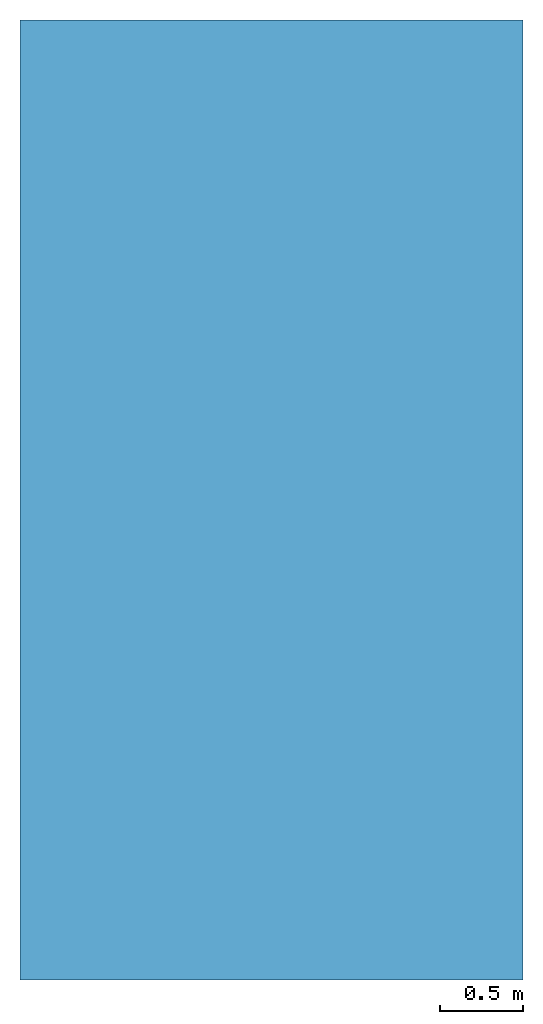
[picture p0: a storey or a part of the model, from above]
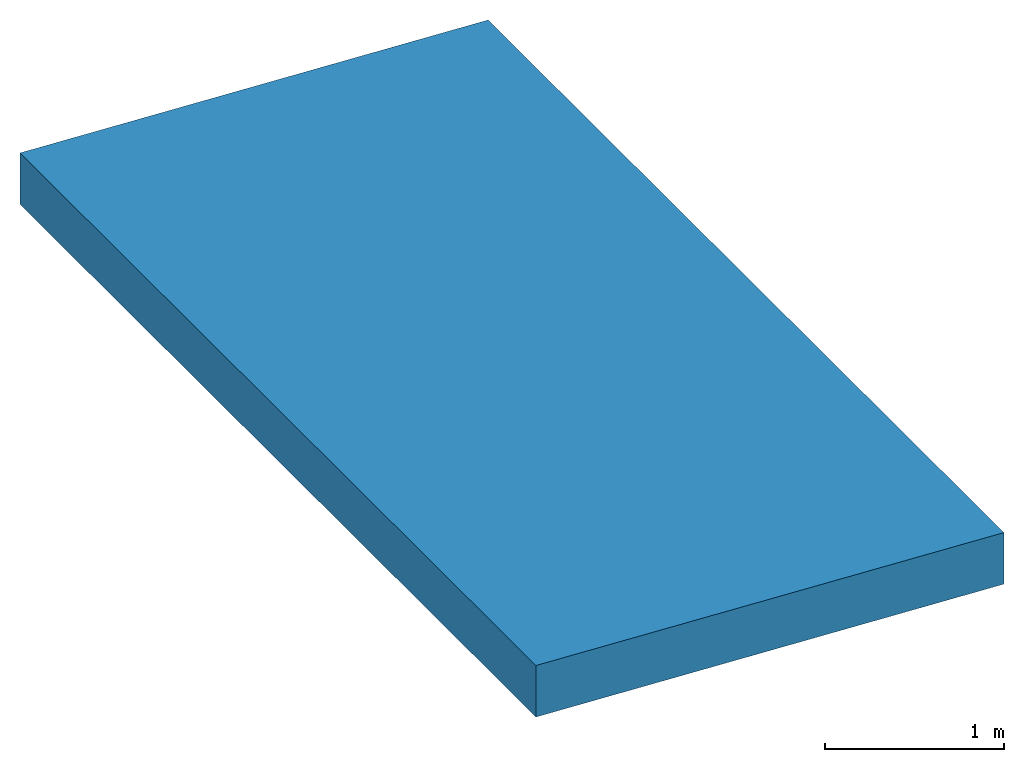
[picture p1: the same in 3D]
Properties of the parts of a building model (IFC2X3)

# File
Description: ViewDefinition [CoordinationView_V2.0], RevitIdentifiers [ContentGUID: b1a34cb4-f0af-4403-8faa-9d45a9ffd249, VersionGUID: 58a498d6-14ff-4763-b198-2685bdfd64d7, NumberOfSaves: 203], CoordinateReference [CoordinateBase: Shared Coordinates]
File name: Kinn servicebygg V9.ifc
Time: 2026-09-17T11:39:23+01:00
Written by: ODA SDAI 25.12
Made in: Autodesk - Revit 26.5.0.55 (ENU) - 26.5.0.55

# IfcProject
LongName: Prosjektnavn; Phase: Prosjektstatus

# IfcSite, Default
RefLatitude: 59, 55, 0, 119999; RefLongitude: 10, 44, 59, 999999; RefElevation: 0 mm

# IfcBuilding
Pset_BuildingCommon - NumberOfStoreys: 8

# IfcBuildingStorey (8)
Pset_AirSideSystemInformation - sets with these values: 2
Name | LongName = Name | Elevation (mm)
Kjeller | Kjeller | -3000
Et. 1 | Et. 1 | 0
Hems plan | Hems plan | 2700
Et. 2 | Et. 2 | 3100
Et. 3 | Et. 3 | 6000
Et. 4 | Et. 4 | 9000
Et. 5 | Et. 5 | 12000
Tak | Tak | 15000

# IfcSpace: Bad 106:843246, 106
In: Et. 1
LongName: Bad; InteriorOrExteriorSpace: INTERNAL
Pset_AirSideSystemInformation - Name: Bad; sets with these values: 2
Pset_SpaceCommon - Reference: Bad 106

# IfcSpace: HCWC 105:843243, 105
In: Et. 1
LongName: HCWC; InteriorOrExteriorSpace: INTERNAL
Pset_AirSideSystemInformation - Name: HCWC; sets with these values: 2
Pset_SpaceCommon - Reference: HCWC 105

# IfcSpace: Lager/tek. 116:884795, 116
In: Et. 1
LongName: Lager/tek.; InteriorOrExteriorSpace: INTERNAL
Pset_AirSideSystemInformation - Name: Lager/tek.; sets with these values: 2
Pset_SpaceCommon - Reference: Lager/tek. 116

# IfcSpace: Oppholdsrom 107:843249, 107
In: Et. 1
LongName: Oppholdsrom; InteriorOrExteriorSpace: INTERNAL
Pset_AirSideSystemInformation - Name: Oppholdsrom; sets with these values: 2
Pset_SpaceCommon - Reference: Oppholdsrom 107

# IfcSpace: WC 101:843231, 101
In: Et. 1
LongName: WC; InteriorOrExteriorSpace: INTERNAL
Pset_AirSideSystemInformation - Name: WC; sets with these values: 2
Pset_SpaceCommon - Reference: WC 101

# IfcSpace: WC 102:843234, 102
In: Et. 1
LongName: WC; InteriorOrExteriorSpace: INTERNAL
Pset_AirSideSystemInformation - Name: WC; sets with these values: 2
Pset_SpaceCommon - Reference: WC 102

# IfcSpace: WC 103:843237, 103
In: Et. 1
LongName: WC; InteriorOrExteriorSpace: INTERNAL
Pset_AirSideSystemInformation - Name: WC; sets with these values: 2
Pset_SpaceCommon - Reference: WC 103

# IfcBeam: Betong Rektangulær:Mønedrager 90x400, Betong Rektangulær:Mønedrager 90x400:924910
In: Et. 1
Type - PredefinedType: BEAM
Type - Pset_BeamCommon - LoadBearing: yes
Material: Tre - Kirsebær
Pset_BeamCommon - IsExternal: no; Slope: 0 deg; Reference: Mønedrager 90x400; Span: 12300 mm
Pset_QuantityTakeOff - Reference: Mønedrager 90x400; sets with these values: 2

# IfcBuildingElementProxy: Hvitevare - Oppvaskmaskin for integrering:600 mm, Hvitevare - Oppvaskmaskin for integrering:600 mm:955397
In: 107
Type - Material: Kjøkken - Hvitevarer
Pset_BuildingElementProxyCommon - Reference: 600 mm; sets with these values: 2

# IfcBuildingElementProxy: RIR_Rør-i-rør_Vegghengt:120x550x500 8rør Ø30, RIR_Rør-i-rør_Vegghengt:120x550x500 8rør Ø30:983592
In: 105
Type - Material: Sort, Hvit
Pset_BuildingElementProxyCommon - Reference: 120x550x500 8rør Ø30; sets with these values: 2

# IfcBuildingElementProxy: Sikringsskap Vegghengt:210x480x920, Sikringsskap Vegghengt:210x480x920:976827
In: 116
Type - Material: Sort, Hvit
Pset_BuildingElementProxyCommon - Reference: 210x480x920; sets with these values: 2

# IfcBuildingElementProxy: Vaskesøyle:Vaskesøyle, Vaskesøyle:Vaskesøyle:884217
In: 106
Type - Material: Bad-Vask-Maskin-Hvit, Stål-Børstet, Plastikk - Sort, Bad-Vask-Maskin-Glass
Pset_BuildingElementProxyCommon - Reference: Vaskesøyle; sets with these values: 2

# IfcColumn: Betong Rektangulær-Søyle:90x90 (6)
In: Et. 1
Type - PredefinedType: COLUMN; Material: Maling mørkegrå(1)
Type - Pset_ColumnCommon - LoadBearing: yes
Pset_ColumnCommon - IsExternal: no; Reference: 90x90; Slope: 0 deg
Pset_QuantityTakeOff - Reference: 90x90; sets with these values: 2
Name (Betong Rektangulær-Søyle:90x90:...)
817801
897383
936991
937197
937405
937572

# IfcCovering: Fascia:Møne, Fascia:Møne:924337
In: Et. 2
Type - Pset_CoveringCommon - Material: Metall - Takrenne
Material: Metall - Takrenne
Pset_CoveringCommon - Reference: Møne; sets with these values: 2

# IfcCovering: Fascia:Vindski (2)
In: Et. 1
Type - Pset_CoveringCommon - Material: Maling mørkegrå(1)
Material: Maling mørkegrå(1)
Pset_CoveringCommon - Reference: Vindski; sets with these values: 2
Name (Fascia:Vindski:...)
857847
906300

# IfcDistributionPort, Port_964572_1
Description: Flow; FlowDirection: SOURCEANDSINK

# IfcDoor: ID Hel:10x21M 2, ID Hel:10x21M 2:897865
In: Et. 1
Type - OperationType: SINGLE_SWING_RIGHT; ParameterTakesPrecedence: no; Sizeable: no; Material: Dør - Håndtak, Tre - Kirsebær
Type - ID Hel:10x21M 2:897865:1 - PanelOperation: SWINGING
OverallHeight: 2100 mm; OverallWidth: 1010 mm
Pset_DoorCommon - IsExternal: no; Reference: 10x21M 2
Pset_QuantityTakeOff - Reference: 10x21M 2

# IfcDoor: YD Glass:10x21M, YD Glass:10x21M:815108
In: Et. 1
Type - OperationType: SINGLE_SWING_RIGHT; ParameterTakesPrecedence: no; Sizeable: no; Material: Dør - Håndtak, Glass - Klart, Maling mørkegrå
Type - YD Glass:10x21M:815108:1 - PanelOperation: SWINGING
OverallHeight: 2090 mm; OverallWidth: 990 mm
Pset_DoorCommon - IsExternal: yes; Reference: 10x21M
Pset_QuantityTakeOff - Reference: 10x21M

# IfcDoor: YD Hel:10x21M (4)
In: Et. 1
Type - OperationType: SINGLE_SWING_LEFT; ParameterTakesPrecedence: no; Sizeable: no; Material: Focus - Dør - Håndtak, Maling mørkegrå, Dør - Terskel - Eik
Type - YD Hel:10x21M:815473:1 - PanelOperation: SWINGING
OverallHeight: 2090 mm; OverallWidth: 990 mm
Pset_DoorCommon - IsExternal: yes; Reference: 10x21M
Pset_QuantityTakeOff - Reference: 10x21M
Name (YD Hel:10x21M:...)
815473
815539
815673
815707

# IfcDoor: YD dobbel hel omramming:18x21M, YD dobbel hel omramming:18x21M:934386
In: Et. 1
Type - OperationType: DOUBLE_DOOR_SINGLE_SWING; ParameterTakesPrecedence: no; Sizeable: no; Material: Focus - Dør - Håndtak, Vegg - Dobbelfals Stående Kledning - Mørkegrå, Focus - Dør - Terskel - Eik
Type - YD dobbel hel omramming:18x21M:934386:1 - PanelOperation: SWINGING
OverallHeight: 2100 mm; OverallWidth: 1810 mm
Pset_DoorCommon - IsExternal: yes; Reference: 18x21M
Pset_QuantityTakeOff - Reference: 18x21M

# IfcFlowSegment: Gutter:Takrenne, Gutter:Takrenne:820507
In: Et. 1
Type - PredefinedType: GUTTER
Pset_DistributionFlowElementCommon - Reference: Takrenne; sets with these values: 2
Pset_FlowSegmentDuctSegment - Length: 26160 mm; sets with these values: 2
Pset_PipeSegmentTypeGutter - Slope: 61.647 deg

# IfcFlowSegment: Gutter:Takrenne beslag, Gutter:Takrenne beslag:820509
In: Et. 1
Type - PredefinedType: GUTTER
Pset_DistributionFlowElementCommon - Reference: Takrenne beslag; sets with these values: 2
Pset_FlowSegmentDuctSegment - Length: 26160 mm; sets with these values: 2
Pset_PipeSegmentTypeGutter - Slope: 0 deg

# IfcFlowTerminal: 7318_IfoSign_vask_500x310_mm_02:Med hanehul i højre side og overløb (3)
Type - Material: Bad-Innredning-Krom, <Unnamed>
Type - Pset_ManufacturerTypeInformation - Manufacturer: Ifö
Pset_DistributionFlowElementCommon - Reference: Med hanehul i højre side og overløb; sets with these values: 2
Name (7318_IfoSign_vask_500x310_mm_02:Med hanehul i højre side og overløb:...) | In
887691 | 103
887748 | 102
887800 | 101

# IfcFlowTerminal: Dusjhjørne_45:900x900mm, Dusjhjørne_45:900x900mm:976009
In: 106
Type - Material: Bad-Innredning-Krom, Bad-Innredning-dusjkabinett-Hvit, Bad-Innredning-Glass-Klar
Pset_DistributionFlowElementCommon - Reference: 900x900mm; sets with these values: 2

# IfcFlowTerminal: Focus - Skyllekar:65,5x50,5, Focus - Skyllekar:65,5x50,5:983081
In: 116
Type - Material: Metall - Polert Fin, Metall - Polert
Pset_DistributionFlowElementCommon - Reference: 65,5x50,5; sets with these values: 2

# IfcFlowTerminal: Focus - Vask:500x350, Focus - Vask:500x350:884095
In: 106
Type - Material: Focus - Material - Krom kran, Focus - Material - WC vask
Pset_DistributionFlowElementCommon - Reference: 500x350; sets with these values: 2

# IfcFlowTerminal: Focus-Toalett Veggmontert 2:Sittehøyde 420 (4)
Type - Material: Focus - VVS - Toalett lokk, Focus - VVS - Krom, Focus - VVS - Toalett
Pset_DistributionFlowElementCommon - Reference: Sittehøyde 420; sets with these values: 2
Name (Focus-Toalett Veggmontert 2:Sittehøyde 420:...) | In
883755 | 106
887868 | 101
887916 | 102
887976 | 103

# IfcFlowTerminal: GARDEN TAP 0153A03-01BVA03:0153A03, GARDEN TAP 0153A03-01BVA03:0153A03:964572
In: Et. 1
Type - Material: Brass, Nickel
Type - Pset_ManufacturerTypeInformation - Manufacturer: SOPAL
Material: Nickel, Chrome, RGB 255-000-000
Pset_DistributionFlowElementCommon - Reference: 0153A03; sets with these values: 2

# IfcFlowTerminal: Klassisk - Kjøkkenvask 1,5 kum:600mm høyre, Klassisk - Kjøkkenvask 1,5 kum:600mm høyre:958605
In: 107
Type - Material: Steel, Chrome Plated, Focus - Kjøkken - Kran, <Unnamed>, Focus - Kjøkken - Vask
Pset_DistributionFlowElementCommon - Reference: 600mm høyre; sets with these values: 2

# IfcFlowTerminal: Toalett HC veggmontert:Toalett HC veggmontert, Toalett HC veggmontert:Toalett HC veggmontert:868754
In: 105
Type - Material: Bad-Innredning-Håndstøtter-Hvit, Focus - VVS - Toalett, Focus - VVS - Toalett lokk, Bad-Innredning-Håndstøtter-Håndtak, Focus - VVS - Krom
Pset_DistributionFlowElementCommon - Reference: Toalett HC veggmontert; sets with these values: 2

# IfcFlowTerminal: VV-Bereder:315_VVB_120, VV-Bereder:315_VVB_120:976469
In: Et. 2
Type - Material: VVS-Bereder-Hvit
Pset_DistributionFlowElementCommon - Reference: 315_VVB_120; sets with these values: 2

# IfcFlowTerminal: Vask HC:600x600, Vask HC:600x600:870789
In: 105
Type - Material: Bad-Innredning-Krom, Bad-Innredning-Porselen
Pset_DistributionFlowElementCommon - Reference: 600x600; sets with these values: 2

# IfcFurnishingElement: Focus - Håndtak Skap:Håndtak skap (7)
In: 107
Type - Material: Focus - Kjøkken - Håndtak
Pset_QuantityTakeOff - Reference: Håndtak skap
Name (Focus - Håndtak Skap:Håndtak skap:...)
860161
860178
898565
905538
905934
907062
907970

# IfcFurnishingElement: Focus - Håndtak Skuff:Håndtak skuff, Focus - Håndtak Skuff:Håndtak skuff:955396
In: 107
Type - Material: Focus - Kjøkken - Håndtak
Pset_QuantityTakeOff - Reference: Håndtak skuff

# IfcFurnishingElement: Focus - Kjøkken - Benkeplate:Focus - Kjøkken - Benkeplate, Focus - Kjøkken - Benkeplate:Focus - Kjøkken - Benkeplate:863563
In: 107
Type - Material: Focus - Material - Benkeplate
Pset_QuantityTakeOff - Reference: Focus - Kjøkken - Benkeplate

# IfcFurnishingElement: Focus - Kjøkken - Benkeskap 1 dør:400 mm, Focus - Kjøkken - Benkeskap 1 dør:400 mm:898564
In: 107
Type - Material: Focus - Kjøkken - Front, Focus - Kjøkken - Skapstamme
Pset_QuantityTakeOff - Reference: 400 mm

# IfcFurnishingElement: Focus - Kjøkken - Benkeskap 1 dør:600 mm (2)
In: 107
Type - Material: Focus - Kjøkken - Front, Focus - Kjøkken - Skapstamme
Pset_QuantityTakeOff - Reference: 600 mm
Name (Focus - Kjøkken - Benkeskap 1 dør:600 mm:...)
860160
860177

# IfcFurnishingElement: Focus - Kjøkken - Oppvaskmaskin Itegrert:600 mm, Focus - Kjøkken - Oppvaskmaskin Itegrert:600 mm:955395
In: 107
Type - Material: Focus - Kjøkken - Front
Pset_QuantityTakeOff - Reference: 600 mm

# IfcFurnishingElement: Focus - Kjøkken - Veggskap 1 dør:400x370x800, Focus - Kjøkken - Veggskap 1 dør:400x370x800:907969
In: 107
Type - Material: Focus - Kjøkken - Front, Focus - Kjøkken - Skapstamme
Pset_QuantityTakeOff - Reference: 400x370x800

# IfcFurnishingElement: Focus - Kjøkken - Veggskap 1 dør:600x370x400 (3)
In: 107
Type - Material: Focus - Kjøkken - Front, Focus - Kjøkken - Skapstamme
Pset_QuantityTakeOff - Reference: 600x370x400
Name (Focus - Kjøkken - Veggskap 1 dør:600x370x400:...)
905537
905933
907061

# IfcOpeningElement: Opening (17)
Name | In
Basic Wall:Finer:896377 | Et. 1 | Pset_OpeningElementCommon - Reference: 10x21M; sets with these values: 2
2 x Basic Wall:Finer:896377 | Et. 1 | Pset_OpeningElementCommon - Reference: 7x21M; sets with these values: 2
Basic Wall:Finer:896772 | Et. 1 | Pset_OpeningElementCommon - Reference: 7x21M; sets with these values: 2
Basic Wall:Innervegg isolert:810342 | Hems plan | Pset_OpeningElementCommon - Reference: Innervegg isolert; sets with these values: 2
Basic Wall:Finer:968378 | Et. 1 | Pset_OpeningElementCommon - Reference: 7x21M; sets with these values: 2
YD Glass:10x21M:815108:1 | Et. 1
YD Hel:10x21M:815473:1 | Et. 1
YD Hel:10x21M:815539:1 | Et. 1
YD Hel:10x21M:815673:1 | Et. 1
YD Hel:10x21M:815707:1 | Et. 1
Hel Rute fast:7x21M:918336:1 | Et. 1
Hel Rute fast:7x21M:918404:1 | Et. 1
YD dobbel hel omramming:18x21M:934386:1 | Et. 1
Hel Rute fast:7x21M:914672:1 | Et. 1
Hel Rute fast:7x21M:913901:1 | Et. 1
ID Hel:10x21M 2:897865:1 | Et. 1

# IfcOpeningElement: Recess (6)
In: Et. 1
Pset_OpeningElementCommon - sets with these values: 2
Name (Basic Wall:Innervegg isolert 200:...) | Reference
811184 | Sittehøyde 420
811184 | 120x550x500 8rør Ø30
3 x 856329 | Sittehøyde 420
856329 | 210x480x920

# IfcRamp: Ramp:Standard Rampe 2, Ramp:Standard Rampe 2:864962
In: Kjeller
Pset_QuantityTakeOff - Reference: Standard Rampe 2
Pset_RampCommon - IsExternal: no; Reference: Standard Rampe 2

# IfcRampFlight, Ramp:Standard Rampe 2:864962:1
In: Kjeller
Material: Betong
Pset_QuantityTakeOff - Reference: Standard Rampe 2; sets with these values: 2

# IfcRoof (4)
In: Et. 2
Pset_RoofCommon - IsExternal: yes
Name (Basic Roof:...) | Material | Pset_QuantityTakeOff, Reference = Pset_RoofCommon, Reference | ProjectedArea (m2) | TotalArea (m2)
Taksperre, Steintekking Sort:808616 | Tak - Takstein - Sort 30 mm, Default Roof 21 mm, Default Roof 36 mm, Tak - Tre - Sperre - Isolert 200 mm, Poche 13 mm | Taksperre, Steintekking Sort | 62.6532 | 73.8793
Taksperre, Steintekking Sort 2:808665 | Tak - Takstein - Sort 50 mm, Default Roof 21 mm, Default Roof 36 mm, Tak - Tre - Sperre - Uisolert 200 mm, Poche 13 mm | Taksperre, Steintekking Sort 2 | 28.449 | 29.4526
Gipsplatetak:935786 | Tak - Gips - Hvit 13 mm | Gipsplatetak | 20.0788 | 23.6765
Gipsplatetak:967629 | Tak - Gips - Hvit 13 mm | Gipsplatetak | 27.2356 | 32.1156

# IfcSlab: Basic Roof:Gipsplatetak (4)
In: Et. 2
Type - PredefinedType: ROOF
Material: Tak - Gips - Hvit 13 mm
Pset_QuantityTakeOff - Reference: Gipsplatetak; sets with these values: 2
Pset_SlabCommon - IsExternal: yes; PitchAngle: 32 deg; Reference: Gipsplatetak
Name (Basic Roof:Gipsplatetak:...)
2 x 935786
2 x 967629

# IfcSlab: Basic Roof:Taksperre, Steintekking Sort (2)
In: Et. 2
Type - PredefinedType: ROOF
Material: Tak - Takstein - Sort 30 mm, Default Roof 21 mm, Default Roof 36 mm, Tak - Tre - Sperre - Isolert 200 mm, Poche 13 mm
Pset_QuantityTakeOff - Reference: Taksperre, Steintekking Sort; sets with these values: 2
Pset_SlabCommon - IsExternal: yes; Reference: Taksperre, Steintekking Sort; PitchAngle: 32 deg

# IfcSlab: Basic Roof:Taksperre, Steintekking Sort 2, Basic Roof:Taksperre, Steintekking Sort 2:808665
In: Et. 2
Type - PredefinedType: ROOF
Material: Tak - Takstein - Sort 50 mm, Default Roof 21 mm, Default Roof 36 mm, Tak - Tre - Sperre - Uisolert 200 mm, Poche 13 mm
Pset_QuantityTakeOff - Reference: Taksperre, Steintekking Sort 2; sets with these values: 2
Pset_SlabCommon - IsExternal: yes; Reference: Taksperre, Steintekking Sort 2; PitchAngle: 15 deg

# IfcSlab: Floor:25-Etasjeskille SpTISp-22_223_23_13, Floor:25-Etasjeskille SpTISp-22_223_23_13:815810
In: Et. 2
Type - PredefinedType: FLOOR; Material: Dekke - Spon 22 mm, Dekke - Bjelke tre - Isolert 223 mm, Dekke - Luftskikt 23 mm, Dekke - Gips 13 mm
Type - Pset_ReinforcementBarPitchOfSlab - Description: Sponplate 22mm, Bjelke 223mm/ Isolasjon 225mm, Lekt 23mm, Gips 13mm
Pset_QuantityTakeOff - Reference: 25-Etasjeskille SpTISp-22_223_23_13; sets with these values: 2
Pset_SlabCommon - LoadBearing: no; IsExternal: no; PitchAngle: 0 deg; Reference: 25-Etasjeskille SpTISp-22_223_23_13

# IfcSlab: Floor:25-Gulv på grunn SpBIhGr-22_50_200_100, Floor:25-Gulv på grunn SpBIhGr-22_50_200_100:809564
In: Et. 1
Type - PredefinedType: FLOOR; Material: Dekke - Spon 22 mm, Dekke - Betong - Plasstøpt - Ubehandlet 50 mm, Dekke - Hard - Isolasjon 200 mm, Betong Plasstøpt - B30 100 mm
Pset_QuantityTakeOff - Reference: 25-Gulv på grunn SpBIhGr-22_50_200_100; sets with these values: 2
Pset_SlabCommon - LoadBearing: no; Reference: 25-Gulv på grunn SpBIhGr-22_50_200_100; IsExternal: no; PitchAngle: 0 deg

# IfcSlab: Floor:25-TbTU-22_148 2, Floor:25-TbTU-22_148 2:809830
In: Et. 1
Type - PredefinedType: FLOOR
Type - Pset_ReinforcementBarPitchOfSlab - Description: Terrassebord 22mm, Bjelke Tre Impregnert 148
Material: Dekke - Terrassebord, Dekke - Terrassebord(1)
Pset_QuantityTakeOff - Reference: 25-TbTU-22_148 2; sets with these values: 2
Pset_SlabCommon - IsExternal: yes; LoadBearing: no; PitchAngle: 0 deg; Reference: 25-TbTU-22_148 2

# IfcSlab: Floor:Steinbenk (3)
In: Et. 1
Type - PredefinedType: FLOOR; Material: Vegg - Naturstein 2 28 mm, Vegg - Naturstein 2 548 mm
Type - Pset_ReinforcementBarPitchOfSlab - Description: Terrassebord 22mm, Bjelke Tre Impregnert 148
Pset_QuantityTakeOff - Reference: Steinbenk; sets with these values: 2
Pset_SlabCommon - IsExternal: yes; LoadBearing: no; PitchAngle: 0 deg; Reference: Steinbenk
Name (Floor:Steinbenk:...)
865549
917861
917933

# IfcSlab: Floor:Steinbenk 2 (2)
In: Et. 1
Type - PredefinedType: FLOOR; Material: Vegg - Naturstein 2 800 mm
Type - Pset_ReinforcementBarPitchOfSlab - Description: Terrassebord 22mm, Bjelke Tre Impregnert 148
Pset_QuantityTakeOff - Reference: Steinbenk 2; sets with these values: 2
Pset_SlabCommon - IsExternal: yes; LoadBearing: no; PitchAngle: 0 deg; Reference: Steinbenk 2
Name (Floor:Steinbenk 2:...)
843945
844043

# IfcWall: Basic Wall:Innervegg isolert, Basic Wall:Innervegg isolert:897807
In: Et. 1
Type - PredefinedType: STANDARD; Material: Vegg - Stender - Isolert 100 mm
Type - Pset_ReinforcementBarPitchOfWall - Description: Betong 200mm
Pset_QuantityTakeOff - Reference: Innervegg isolert; sets with these values: 2
Pset_WallCommon - LoadBearing: no; IsExternal: no; ExtendToStructure: yes; Reference: Innervegg isolert

# IfcWallStandardCase: Basic Wall:Betongsåle, Basic Wall:Betongsåle:815924
In: Et. 1
Type - PredefinedType: STANDARD; Material: Vegg - Betong - Element - Ubehandlet 300 mm
Type - Pset_ReinforcementBarPitchOfWall - Description: Lettklinker 250mm
Pset_QuantityTakeOff - Reference: Betongsåle; sets with these values: 2
Pset_WallCommon - IsExternal: yes; ExtendToStructure: no; LoadBearing: no; Reference: Betongsåle

# IfcWallStandardCase: Basic Wall:Bjelke 2, Basic Wall:Bjelke 2:817206
In: Et. 2
Type - PredefinedType: STANDARD; Material: Maling mørkegrå(1) 120 mm
Type - Pset_ReinforcementBarPitchOfWall - Description: Utvendig isolasjon 100mm
Pset_QuantityTakeOff - Reference: Bjelke 2; sets with these values: 2
Pset_WallCommon - IsExternal: yes; LoadBearing: no; ExtendToStructure: yes; Reference: Bjelke 2

# IfcWallStandardCase: Basic Wall:Finer (3)
In: Et. 1
Type - PredefinedType: STANDARD; Material: Tre - Kirsebær 12 mm
Type - Pset_ReinforcementBarPitchOfWall - Description: Betong 200mm
Pset_QuantityTakeOff - Reference: Finer; sets with these values: 2
Pset_WallCommon - LoadBearing: no; IsExternal: no; ExtendToStructure: yes; Reference: Finer
Name (Basic Wall:Finer:...)
896377
896772
968378

# IfcWallStandardCase: Basic Wall:Foring (2)
In: Et. 1
Type - PredefinedType: STANDARD; Material: Tre - Kirsebær 10 mm
Type - Pset_ReinforcementBarPitchOfWall - Description: Betong 200mm
Pset_QuantityTakeOff - Reference: Foring; sets with these values: 2
Pset_WallCommon - ExtendToStructure: no; LoadBearing: no; IsExternal: no; Reference: Foring
Name (Basic Wall:Foring:...)
966636
966912

# IfcWallStandardCase: Basic Wall:Innervegg isolert (7)
Type - PredefinedType: STANDARD; Material: Vegg - Stender - Isolert 100 mm
Type - Pset_ReinforcementBarPitchOfWall - Description: Betong 200mm
Pset_QuantityTakeOff - Reference: Innervegg isolert; sets with these values: 2
Pset_WallCommon - LoadBearing: no; IsExternal: no; ExtendToStructure: yes; Reference: Innervegg isolert
Name (Basic Wall:Innervegg isolert:...) | In
810524 | Et. 1
810685 | Et. 1
811058 | Et. 1
856168 | Et. 1
897714 | Et. 1
898983 | Et. 1
938566 | Hems plan

# IfcWallStandardCase: Basic Wall:Innervegg isolert 200 (2)
In: Et. 1
Type - PredefinedType: STANDARD; Material: Vegg - Stender - Isolert 200 mm
Type - Pset_ReinforcementBarPitchOfWall - Description: Betong 200mm
Pset_QuantityTakeOff - Reference: Innervegg isolert 200; sets with these values: 2
Pset_WallCommon - LoadBearing: no; IsExternal: no; ExtendToStructure: yes; Reference: Innervegg isolert 200
Name (Basic Wall:Innervegg isolert 200:...)
811184
856329

# IfcWallStandardCase: Basic Wall:Yttervegg liggende kl grå (4)
In: Et. 2
Type - PredefinedType: STANDARD; Material: Vegg - Liggende Kledning - GRÅ 19 mm, Default Floor 48 mm, Default Floor 48 mm, Default Floor 12 mm, Vegg - Stender - Isolert 150 mm
Type - Pset_ReinforcementBarPitchOfWall - Description: Utvendig isolasjon 100mm
Pset_QuantityTakeOff - Reference: Yttervegg liggende kl grå; sets with these values: 2
Pset_WallCommon - IsExternal: yes; LoadBearing: no; Reference: Yttervegg liggende kl grå; ExtendToStructure: yes
Name (Basic Wall:Yttervegg liggende kl grå:...)
810018
810020
810021
843892

# IfcWallStandardCase: Basic Wall:Yttervegg stående kl (4)
In: Et. 1
Type - PredefinedType: STANDARD; Material: Vegg - Dobbelfals Stående Kledning - Mørkegrå 19 mm, Default Floor 36 mm, Default Floor 23 mm, Default Floor 12 mm, Vegg - Stender - Isolert 150 mm
Type - Pset_ReinforcementBarPitchOfWall - Description: Utvendig isolasjon 100mm
Pset_QuantityTakeOff - Reference: Yttervegg stående kl; sets with these values: 2
Pset_WallCommon - Reference: Yttervegg stående kl; IsExternal: yes; ExtendToStructure: no; LoadBearing: no
Name (Basic Wall:Yttervegg stående kl:...)
808336
808421
808487
808551

# IfcWindow: Hel Rute fast:7x21M (4)
In: Et. 1
Type - ParameterTakesPrecedence: no; Sizeable: no; Material: Focus - Glass - Klart, Maling mørkegrå
OverallHeight: 2090 mm; OverallWidth: 690 mm
Pset_QuantityTakeOff - Reference: 7x21M
Pset_WindowCommon - IsExternal: yes; Reference: 7x21M
Name (Hel Rute fast:7x21M:...)
913901
914672
918336
918404
